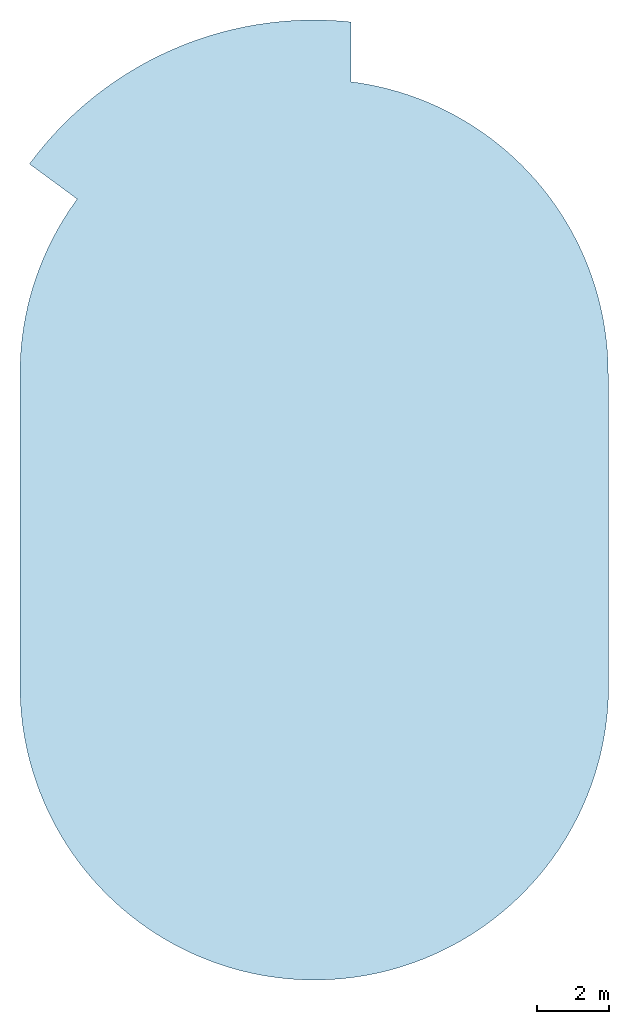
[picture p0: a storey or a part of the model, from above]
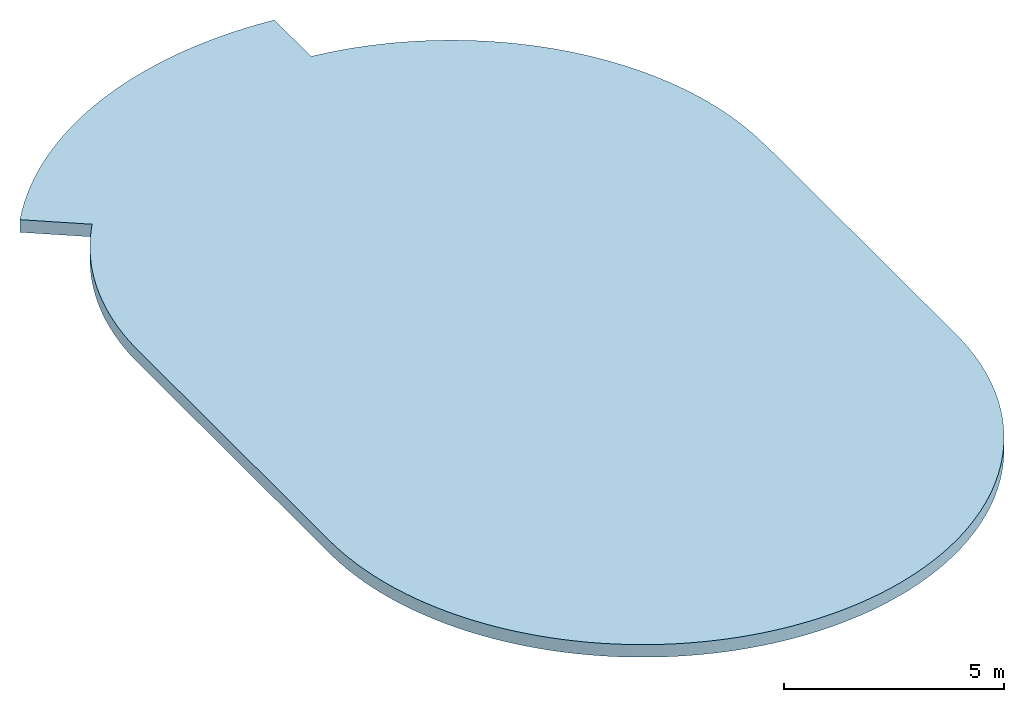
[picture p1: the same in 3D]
Properties of the parts of a building model (IFC4)

# File
Description: ViewDefinition [ReferenceView_V1.2], ExchangeRequirement [Architecture], Option [Elements to export: Visible elements (on all stories)], Option [Partial Structure Display: Entire Model], Option [IFC Domain: All], Option [Structural Function: All Elements], Option [Convert Grid elements: On], Option [Convert IFC Annotations and Archicad 2D elements: Off], Option [Convert 2D symbols of Doors and Windows: Off], Option [Export geometries that Participates in Collision Detection only: On], Option [Split complex elements: Off], Option [Material Preservation: Explode where necessary], Option [IFC Model position: Survey Point and Project Origin], Option [Curtain Wall export mode: Single Element], Option [Railing export mode: Single Element], Option [Stair export mode: Single Element], Option [Properties To Export: All properties], Option [Space containment: On], Option [IFC Domain For Space Containment: All], Option [Geometry to type objects: Off], Option [Element Properties: Off], Option [Building Material Properties: Off], Option [Element Parameters: Off], Option [Component Parameters: Off], Option [IFC Base Quantities: On], Option [Door Window Parameters: On], Option [IFC Space boundaries: On], Option [Archicad Zone Categories as IFC Space classification data: Off], Option [Element Classifications: Off]
File name: C:\Users\micel\OneDrive\Dokumenty\ŠKOLA\!!4.LS!!\BAKALÁŘKA\Publikace\Nová složka\LES24-PST-ZZ-M3-Vodorovne_nosne_kce.ifc
Time: 2024-05-22T15:31:06
Author: Architect
Organization: Building Designer Office
Written by: DDS_IFC v3.0
Made in: IFC file generated by Graphisoft Archicad 27.0.0 CZE FULL Windows version (IFC add-on version: 3001 CZE FULL).
Authorization: The authorising person

# IfcProject, Univerzitní lezecké centrum
Description: BIM projekt - bakalářská práce

# IfcSite, Exteriér
RefLatitude: 50, 1, 18, 339575; RefLongitude: 15, 46, 11, 568244; RefElevation: 221783 mm
Qto_SiteBaseQuantities - GrossPerimeter: 0 mm; GrossArea: 3562 m2

# IfcBuilding, Univerzitní lezecké centrum
Qto_BuildingBaseQuantities - GrossFloorArea: 0 m2

# IfcBuildingStorey (4)
In: Univerzitní lezecké centrum
Qto_BuildingStoreyBaseQuantities - GrossFloorArea: 0 m2
Name | Elevation (mm) | NetHeight (mm) = GrossHeight (mm)
3.NP | 6400 | 3200
1.NP | 0 | 3200
ZÁKLADY | -4070 | 720
4.NP | 9600 | 3200

# IfcBeam: Dřevotříska 300 x 30
In: 4.NP
Type - PredefinedType: BEAM
Material: Dřevotříska
Pset_BeamCommon - Span: 4500 mm; Slope: 0 deg; IsExternal: no; Status: EXISTING; LoadBearing: yes; Reference: Dřevotříska 300 x 30
Qto_BeamBaseQuantities - Length: 4499.97 mm; CrossSectionArea: 0.00900001 m2; OuterSurfaceArea: 2.96998 m2; GrossSurfaceArea: 2.98798 m2; GrossVolume: 0.0404998 m3; NetSurfaceArea: 2.98798 m2; NetVolume: 0.0404998 m3
Pset_ManufacturerOccurrence - AcquisitionDate: DD.MM.RRRR

# IfcBeam: Ocel - konstrukční 100 x 220 (2)
In: 4.NP
Type - PredefinedType: BEAM
Material: Ocel - konstrukční
Pset_BeamCommon - Span: 4500 mm; Slope: 0 deg; IsExternal: no; Status: EXISTING; LoadBearing: yes; Reference: Ocel - konstrukční 100 x 220
Qto_BeamBaseQuantities - Length: 5120 mm; CrossSectionArea: 0.022 m2; OuterSurfaceArea: 3.2768 m2; GrossSurfaceArea: 3.3208 m2; GrossVolume: 0.11264 m3; NetSurfaceArea: 3.3208 m2; NetVolume: 0.11264 m3
Pset_ManufacturerOccurrence - AcquisitionDate: DD.MM.RRRR
Name
Pk04-1
Pk04-3

# IfcSlab: Beton vyztužený stropy 150, D07
In: 4.NP
Type - PredefinedType: FLOOR
Material: Beton vyztužený stropy
Pset_SlabCommon - Status: EXISTING; LoadBearing: yes
Třída pevnosti - Popis: Železobetonová stropní deska, třída betonu C25/30 XC1, vyztuženo dle statického řešení stavby; Třída pevnosti: C25/30
Pset_ManufacturerOccurrence - AcquisitionDate: DD.MM.RRRR
Qto_SlabBaseQuantities - Width: 150 mm; Perimeter: 20854.8 mm; GrossArea: 29.9674 m2; NetArea: 29.9674 m2; GrossVolume: 4.49512 m3; NetVolume: 4.49512 m3; Beton vyztužený stropy, Width: 150 mm

# IfcSlab: Beton vyztužený stropy 200 (2)
Type - PredefinedType: FLOOR
Material: Beton vyztužený stropy
Qto_SlabBaseQuantities - Width: 200 mm; Beton vyztužený stropy, Width: 200 mm
Pset_ManufacturerOccurrence - AcquisitionDate: DD.MM.RRRR
Pset_SlabCommon - Status: EXISTING; LoadBearing: yes
Třída pevnosti - Popis: Železobetonová stropní deska, třída betonu C25/30 XC1, vyztuženo dle statického řešení stavby; Třída pevnosti: C25/30
Name | In | Perimeter (mm) | GrossArea (m2) = NetArea (m2) | GrossVolume (m3) = NetVolume (m3)
D02 | 1.NP | 56615.5 | 179.285 | 35.8571
D04 | 3.NP | 50438.1 | 89.0296 | 17.8059

# IfcSlab: Beton vyztužený základová deska 350, D01
In: ZÁKLADY
Type - PredefinedType: FLOOR
Material: Beton vyztužený základová deska
Pset_SlabCommon - Status: EXISTING; LoadBearing: yes
Třída pevnosti - Třída pevnosti: C20/25; Popis: Železobetonová základová deska, třída betonu C20/25 XC1, S3, Dmax=22 mm, vyztuženo dle statického řešení stavby
Pset_ManufacturerOccurrence - AcquisitionDate: DD.MM.RRRR
Qto_SlabBaseQuantities - Width: 350 mm; Perimeter: 73775.9 mm; GrossArea: 369.44 m2; NetArea: 369.44 m2; GrossVolume: 129.304 m3; NetVolume: 129.304 m3; Beton vyztužený základová deska, Width: 350 mm
